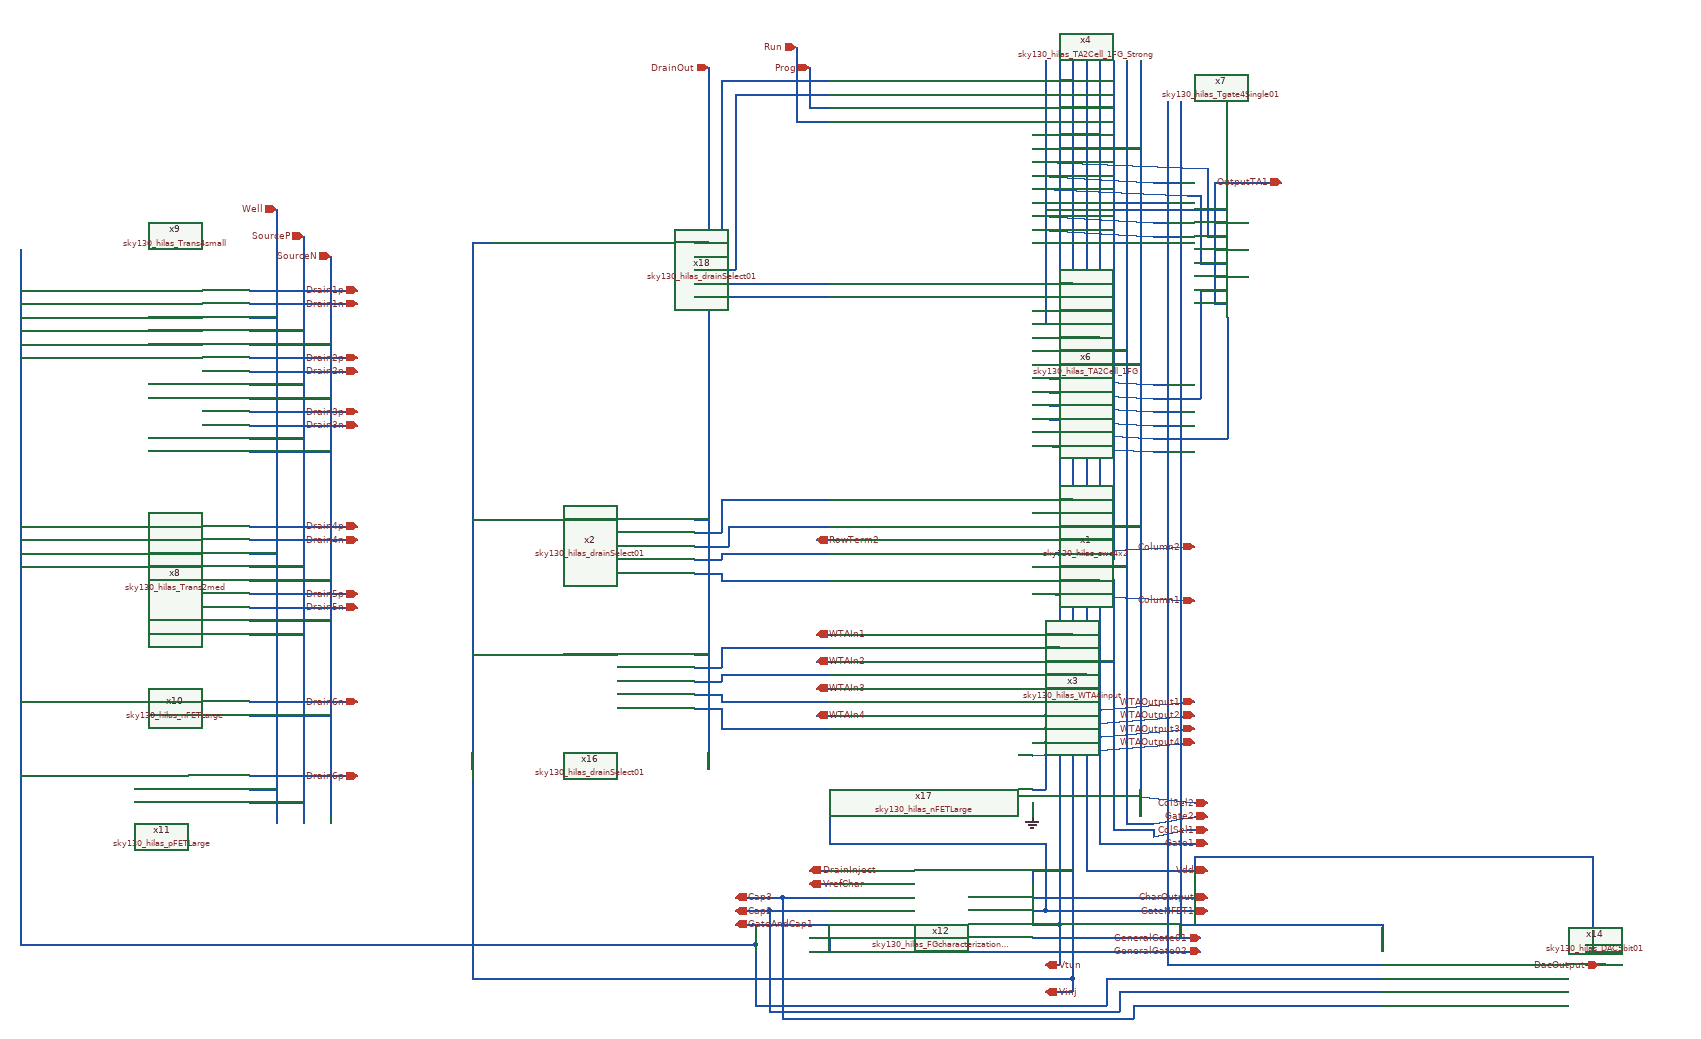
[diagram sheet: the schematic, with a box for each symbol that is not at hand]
v {xschem version=2.9.9 file_version=1.2 }
G {}
K {}
V {}
S {}
E {}
N 370 -10 370 440 { lab=Vtun}
N -500 -10 -500 430 { lab=Vinj}
N 390 -10 390 440 { lab=Vinj}
N -500 60 -470 60 { lab=Vinj}
N -500 260 -470 260 { lab=Vinj}
N 330 30 390 30 { lab=Vinj}
N 330 230 390 230 { lab=Vinj}
N 330 50 370 50 { lab=Vtun}
N 330 250 370 250 { lab=Vtun}
N 410 -10 410 440 { lab=Vdd}
N 330 290 410 290 { lab=Vdd}
N 330 480 330 500 { lab=GND}
N 330 330 350 330 { lab=#net1}
N 350 330 350 460 { lab=#net1}
N 330 460 350 460 { lab=#net1}
N -150 -10 -150 430 { lab=DrainOut}
N -170 60 -150 60 { lab=DrainOut}
N -170 260 -150 260 { lab=DrainOut}
N -130 30 30 30 { lab=#net2}
N -130 30 -130 80 { lab=#net2}
N -170 80 -130 80 { lab=#net2}
N -130 150 30 150 { lab=#net3}
N -130 140 -130 150 { lab=#net3}
N -170 140 -130 140 { lab=#net3}
N -130 110 30 110 { lab=#net4}
N -130 110 -130 120 { lab=#net4}
N -170 120 -130 120 { lab=#net4}
N -120 70 30 70 { lab=#net5}
N -120 70 -120 100 { lab=#net5}
N -170 100 -120 100 { lab=#net5}
N -130 250 30 250 { lab=#net6}
N -130 370 30 370 { lab=#net7}
N -110 330 30 330 { lab=#net8}
N -110 290 30 290 { lab=#net9}
N -170 280 -130 280 { lab=#net6}
N -130 250 -130 280 { lab=#net6}
N -170 340 -130 340 { lab=#net7}
N -130 340 -130 370 { lab=#net7}
N -130 330 -110 330 { lab=#net8}
N -130 320 -130 330 { lab=#net8}
N -170 320 -130 320 { lab=#net8}
N -130 290 -110 290 { lab=#net9}
N -130 290 -130 300 { lab=#net9}
N -170 300 -130 300 { lab=#net9}
N 430 -10 430 500 { lab=Gate1}
N 470 -10 470 500 { lab=Gate2}
N 330 310 430 310 { lab=Gate1}
N 330 150 430 150 { lab=Gate1}
N 330 130 450 130 { lab=Gate2}
N 490 -10 490 500 { lab=ColSel2}
N 450 130 470 130 { lab=Gate2}
N 450 -10 450 120 { lab=ColSel1}
N 450 150 450 500 { lab=ColSel1}
N 330 90 450 90 { lab=ColSel1}
N 330 270 450 270 { lab=ColSel1}
N 330 70 490 70 { lab=ColSel2}
N 440 120 450 150 { lab=ColSel1}
N 440 120 450 120 { lab=ColSel1}
N -500 420 -500 550 { lab=Vinj}
N -500 740 390 740 { lab=Vinj}
N 390 440 390 550 { lab=Vinj}
N 390 550 390 720 { lab=Vinj}
N -500 550 -500 720 { lab=Vinj}
N 370 440 370 660 { lab=Vtun}
N 330 660 370 660 { lab=Vtun}
N 330 580 390 580 { lab=Vinj}
N 390 720 390 740 { lab=Vinj}
N 370 660 370 720 { lab=Vtun}
N 350 720 370 720 { lab=Vtun}
N 390 740 390 760 { lab=Vinj}
N 350 760 390 760 { lab=Vinj}
N 30 460 30 540 { lab=GateNFET1}
N 30 540 350 540 { lab=GateNFET1}
N 350 540 350 640 { lab=GateNFET1}
N 330 640 350 640 { lab=GateNFET1}
N 350 640 590 640 { lab=GateNFET1}
N 330 620 570 620 { lab=CharOutput}
N 330 580 330 600 { lab=Vinj}
N 0 700 330 700 { lab=GeneralGate02}
N -0 680 30 680 { lab=GeneralGate02}
N -0 660 30 660 { lab=GateAndCap1}
N -0 640 30 640 { lab=Cap2}
N -0 620 30 620 { lab=Cap3}
N -0 600 30 600 { lab=VrefChar}
N 0 580 30 580 { lab=DrainInject}
N 370 -520 370 -70 { lab=Vtun}
N 390 -520 390 -70 { lab=Vinj}
N 410 -520 410 -70 { lab=Vdd}
N 430 -520 430 -10 { lab=Gate1}
N 470 -520 470 -10 { lab=Gate2}
N 490 -520 490 -10 { lab=ColSel2}
N 450 -520 450 -10 { lab=ColSel1}
N 370 -70 370 -10 { lab=Vtun}
N 390 -70 390 -10 { lab=Vinj}
N 410 -70 410 -10 { lab=Vdd}
N -150 -450 -150 -10 { lab=DrainOut}
N -150 -610 -150 -450 { lab=DrainOut}
N -170 -350 -150 -350 { lab=DrainOut}
N -130 -270 30 -270 { lab=#net10}
N -130 -290 30 -290 { lab=#net11}
N -170 -290 -130 -290 { lab=#net11}
N -170 -270 -130 -270 { lab=#net10}
N -500 -350 -500 -10 { lab=Vinj}
N -500 -350 -470 -350 { lab=Vinj}
N -0 -610 -0 -550 { lab=Prog}
N -20 -610 -20 -530 { lab=Run}
N 0 -550 30 -550 { lab=Prog}
N -20 -530 30 -530 { lab=Run}
N -170 -330 -130 -330 { lab=#net12}
N -130 -590 -130 -330 { lab=#net12}
N -130 -590 30 -590 { lab=#net12}
N -170 -310 -110 -310 { lab=#net13}
N -110 -570 -110 -310 { lab=#net13}
N -110 -570 30 -570 { lab=#net13}
N 370 -620 370 -520 { lab=Vtun}
N 390 -620 390 -520 { lab=Vinj}
N 410 -620 410 -520 { lab=Vdd}
N 430 -620 430 -520 { lab=Gate1}
N 450 -620 450 -520 { lab=ColSel1}
N 470 -620 470 -520 { lab=Gate2}
N 490 -620 490 -520 { lab=ColSel2}
N 330 -590 390 -590 { lab=Vinj}
N 330 -570 370 -570 { lab=Vtun}
N 330 -290 390 -290 { lab=Vinj}
N 330 -270 370 -270 { lab=Vtun}
N 330 -250 450 -250 { lab=ColSel1}
N 330 -550 450 -550 { lab=ColSel1}
N 330 -490 490 -490 { lab=ColSel2}
N 330 -170 490 -170 { lab=ColSel2}
N 330 -510 430 -510 { lab=Gate1}
N 330 -210 430 -210 { lab=Gate1}
N 330 -190 470 -190 { lab=Gate2}
N 330 -350 470 -350 { lab=Gate2}
N 350 -620 350 -230 { lab=#net14}
N 330 -230 350 -230 { lab=#net14}
N 330 -530 350 -530 { lab=#net14}
N 600 -440 600 -260 { lab=OutputTA1}
N 600 -260 620 -260 { lab=OutputTA1}
N 600 -300 620 -300 { lab=OutputTA1}
N 600 -340 620 -340 { lab=OutputTA1}
N 600 -380 620 -380 { lab=OutputTA1}
N 350 -400 620 -400 { lab=#net14}
N 620 -240 620 -60 { lab=#net15}
N 330 -70 350 -70 { lab=#net15}
N 350 -70 510 -60 { lab=#net15}
N 510 -60 620 -60 { lab=#net15}
N 330 -130 510 -120 { lab=#net16}
N 510 -120 580 -120 { lab=#net16}
N 580 -280 580 -120 { lab=#net16}
N 580 -280 620 -280 { lab=#net16}
N 590 -460 590 -360 { lab=#net17}
N 330 -470 590 -460 { lab=#net17}
N 330 -430 560 -420 { lab=#net18}
N 590 -360 620 -360 { lab=#net17}
N 580 -320 620 -320 { lab=#net18}
N 580 -420 580 -320 { lab=#net18}
N 560 -420 580 -420 { lab=#net18}
N 600 -440 680 -440 { lab=OutputTA1}
N 680 -440 700 -440 { lab=OutputTA1}
N 330 680 580 680 { lab=GeneralGate01}
N 330 700 580 700 { lab=GeneralGate02}
N 30 680 30 700 { lab=GeneralGate02}
N 570 620 590 620 { lab=CharOutput}
N 530 -560 530 520 { lab=GeneralGate02}
N 550 -560 550 520 { lab=GeneralGate01}
N 550 520 550 680 { lab=GeneralGate01}
N 530 520 530 700 { lab=GeneralGate02}
N 410 440 410 580 { lab=Vdd}
N 410 580 590 580 { lab=Vdd}
N -500 720 -500 740 { lab=Vinj}
N 330 -50 510 -40 { lab=GeneralGate02}
N 510 -40 530 -40 { lab=GeneralGate02}
N 330 -90 510 -80 { lab=GeneralGate01}
N 510 -80 550 -80 { lab=GeneralGate01}
N 330 -110 510 -100 { lab=GeneralGate01}
N 510 -100 550 -100 { lab=GeneralGate01}
N 330 -150 510 -140 { lab=GeneralGate02}
N 510 -140 530 -140 { lab=GeneralGate02}
N 330 -450 510 -440 { lab=GeneralGate01}
N 510 -440 550 -440 { lab=GeneralGate01}
N 330 -370 510 -360 { lab=GeneralGate01}
N 510 -360 550 -360 { lab=GeneralGate01}
N 330 -390 510 -380 { lab=GeneralGate02}
N 510 -380 530 -380 { lab=GeneralGate02}
N 330 -410 530 -410 { lab=GeneralGate02}
N 430 540 590 540 { lab=Gate1}
N 430 500 430 540 { lab=Gate1}
N 450 500 450 520 { lab=ColSel1}
N 450 520 510 520 { lab=ColSel1}
N 470 500 470 510 { lab=Gate2}
N 470 510 510 510 { lab=Gate2}
N 570 480 590 480 { lab=ColSel2}
N 490 470 570 480 { lab=ColSel2}
N 570 500 590 500 { lab=Gate2}
N 510 510 570 500 { lab=Gate2}
N 560 520 590 520 { lab=ColSel1}
N 510 530 560 520 { lab=ColSel1}
N 510 520 510 530 { lab=ColSel1}
N -1170 -340 -1170 510 { lab=GateAndCap1}
N -1170 -280 -1130 -280 { lab=GateAndCap1}
N -1170 -260 -1130 -260 { lab=GateAndCap1}
N -1170 -240 -1130 -240 { lab=GateAndCap1}
N -1170 -220 -1130 -220 { lab=GateAndCap1}
N -1170 -200 -1130 -200 { lab=GateAndCap1}
N -1170 -180 -1130 -180 { lab=GateAndCap1}
N -1170 70 -1130 70 { lab=GateAndCap1}
N -1170 90 -1130 90 { lab=GateAndCap1}
N -1170 110 -1130 110 { lab=GateAndCap1}
N -1170 130 -1130 130 { lab=GateAndCap1}
N -1170 330 -1130 330 { lab=GateAndCap1}
N -1170 440 -1130 440 { lab=GateAndCap1}
N -790 -310 -790 510 { lab=Well}
N -750 -310 -750 510 { lab=SourceP}
N -710 -310 -710 500 { lab=SourceN}
N -830 -240 -790 -240 { lab=Well}
N -830 110 -790 110 { lab=Well}
N -830 460 -790 460 { lab=Well}
N -830 -220 -750 -220 { lab=SourceP}
N -830 -200 -710 -200 { lab=SourceN}
N -830 -140 -750 -140 { lab=SourceP}
N -830 -120 -710 -120 { lab=SourceN}
N -830 -60 -750 -60 { lab=SourceP}
N -830 -40 -710 -40 { lab=SourceN}
N -830 130 -750 130 { lab=SourceP}
N -830 150 -710 150 { lab=SourceN}
N -830 230 -750 230 { lab=SourceP}
N -830 210 -710 210 { lab=SourceN}
N -830 350 -710 350 { lab=SourceN}
N -830 480 -750 480 { lab=SourceP}
N -110 660 0 660 { lab=GateAndCap1}
N -80 660 -80 690 { lab=GateAndCap1}
N -470 690 -80 690 { lab=GateAndCap1}
N -540 690 -470 690 { lab=GateAndCap1}
N -1170 690 -540 690 { lab=GateAndCap1}
N -1170 510 -1170 690 { lab=GateAndCap1}
N -830 -280 -670 -280 { lab=Drain1p}
N -830 -260 -670 -260 { lab=Drain1n}
N -830 -180 -670 -180 { lab=Drain2p}
N -830 -160 -670 -160 { lab=Drain2n}
N -830 -100 -670 -100 { lab=Drain3p}
N -830 -80 -670 -80 { lab=Drain3n}
N -830 70 -670 70 { lab=Drain4p}
N -830 90 -670 90 { lab=Drain4n}
N -830 170 -670 170 { lab=Drain5p}
N -830 190 -670 190 { lab=Drain5n}
N -830 330 -670 330 { lab=Drain6n}
N -830 440 -670 440 { lab=Drain6p}
N -710 -330 -710 -310 { lab=SourceN}
N -750 -360 -750 -310 { lab=SourceP}
N -790 -400 -790 -310 { lab=Well}
N -20 -640 -20 -610 { lab=Run}
N 10 270 30 270 { lab=WTAIn2}
N 10 230 30 230 { lab=WTAIn1}
N 10 310 30 310 { lab=WTAIn3}
N 10 350 30 350 { lab=WTAIn4}
N 330 110 570 100 { lab=Column2}
N 330 170 570 180 { lab=Column1}
N 570 560 570 580 { lab=Vdd}
N 570 560 1160 560 { lab=Vdd}
N 1160 560 1160 690 { lab=Vdd}
N 1150 690 1160 690 { lab=Vdd}
N 550 660 850 660 { lab=GeneralGate01}
N 530 700 530 720 { lab=GeneralGate02}
N 530 720 840 720 { lab=GeneralGate02}
N 840 720 850 720 { lab=GeneralGate02}
N 850 660 850 700 { lab=GeneralGate01}
N 1150 700 1160 700 { lab=Vdd}
N 1160 670 1160 700 { lab=Vdd}
N 440 740 850 740 { lab=GateAndCap1}
N 440 740 440 780 { lab=GateAndCap1}
N -80 780 440 780 { lab=GateAndCap1}
N -80 690 -80 780 { lab=GateAndCap1}
N 460 760 850 760 { lab=Cap2}
N 460 760 460 790 { lab=Cap2}
N -60 790 460 790 { lab=Cap2}
N -60 640 -60 790 { lab=Cap2}
N -60 640 -0 640 { lab=Cap2}
N -110 640 -60 640 { lab=Cap2}
N 480 780 850 780 { lab=Cap3}
N 480 780 480 800 { lab=Cap3}
N -40 800 480 800 { lab=Cap3}
N -40 620 -40 800 { lab=Cap3}
N -40 620 0 620 { lab=Cap3}
N -110 620 -40 620 { lab=Cap3}
N 1150 720 1180 720 { lab=DacOutput}
N 330 350 570 330 { lab=WTAOutput1}
N 330 370 570 350 { lab=WTAOutput2}
N 330 390 570 370 { lab=WTAOutput3}
N 330 410 570 390 { lab=WTAOutput4}
N 10 90 30 90 { lab=RowTerm2}
C {sky130_hilas_swc4x2.sym} 180 100 0 0 {name=x1}
C {sky130_hilas_drainSelect01.sym} -320 100 0 0 {name=x2}
C {sky130_hilas_WTA4input.sym} 180 320 0 0 {name=x3}
C {sky130_hilas_TA2Cell_1FG_Strong.sym} 180 -470 0 0 {name=x4}
C {sky130_hilas_TA2Cell_1FG.sym} 180 -170 0 0 {name=x6}
C {sky130_hilas_Tgate4Single01.sym} 770 -320 0 1 {name=x7}
C {sky130_hilas_Trans2med.sym} -980 150 0 0 {name=x8}
C {sky130_hilas_Trans4small.sym} -980 -160 0 0 {name=x9}
C {sky130_hilas_nFETLarge.sym} -980 340 0 0 {name=x10}
C {sky130_hilas_pFETLarge.sym} -980 460 0 0 {name=x11}
C {sky130_hilas_FGcharacterization01.sym} 180 630 0 0 {name=x12}
C {sky130_hilas_DAC5bit01.sym} 1000 740 0 0 {name=x14}
C {sky130_hilas_drainSelect01.sym} -320 300 0 0 {name=x16}
C {devices/gnd.sym} 330 500 0 0 {name=l1 lab=GND}
C {sky130_hilas_nFETLarge.sym} 180 470 0 0 {name=x17}
C {sky130_hilas_drainSelect01.sym} -320 -310 0 0 {name=x18}
C {devices/iopin.sym} 350 720 0 1 {name=Vtun lab=Vtun}
C {devices/iopin.sym} 350 760 0 1 {name=Vinj lab=Vinj}
C {devices/iopin.sym} 590 640 0 0 {name=GateNFET1 lab=GateNFET1}
C {devices/iopin.sym} 590 620 0 0 {name=CharOutput lab=CharOutput}
C {devices/iopin.sym} 0 580 0 1 {name=DrainInject lab=DrainInject}
C {devices/iopin.sym} 0 600 0 1 {name=VrefChar lab=VrefChar}
C {devices/iopin.sym} -110 620 0 1 {name=Cap3 lab=Cap3}
C {devices/iopin.sym} -110 640 0 1 {name=Cap2 lab=Cap2}
C {devices/iopin.sym} -110 660 0 1 {name=GateAndCap1 lab=GateAndCap1}
C {devices/iopin.sym} 580 680 0 0 {name=GeneralGate01 lab=GeneralGate01}
C {devices/iopin.sym} 580 700 0 0 {name=GeneralGate02 lab=GeneralGate02}
C {devices/iopin.sym} 700 -440 0 0 {name=OutputTA1 lab=OutputTA1}
C {devices/iopin.sym} 590 580 0 0 {name=Vdd lab=Vdd}
C {devices/iopin.sym} 590 540 0 0 {name=Gate1 lab=Gate1}
C {devices/iopin.sym} 590 520 0 0 {name=ColSel1 lab=ColSel1}
C {devices/iopin.sym} 590 500 0 0 {name=Gate2 lab=Gate2}
C {devices/iopin.sym} 590 480 0 0 {name=ColSel2 lab=ColSel2}
C {devices/iopin.sym} -670 -280 0 0 {name=Drain1p lab=Drain1p}
C {devices/iopin.sym} -670 -260 0 0 {name=Drain1n lab=Drain1n}
C {devices/iopin.sym} -670 -180 0 0 {name=Drain2p lab=Drain2p}
C {devices/iopin.sym} -670 -160 0 0 {name=Drain2n lab=Drain2n}
C {devices/iopin.sym} -670 -100 0 0 {name=Drain3p lab=Drain3p}
C {devices/iopin.sym} -670 -80 0 0 {name=Drain3n lab=Drain3n}
C {devices/iopin.sym} -670 70 0 0 {name=Drain4p lab=Drain4p}
C {devices/iopin.sym} -670 90 0 0 {name=Drain4n lab=Drain4n}
C {devices/iopin.sym} -670 170 0 0 {name=Drain5p lab=Drain5p}
C {devices/iopin.sym} -670 190 0 0 {name=Drain5n lab=Drain5n}
C {devices/iopin.sym} -670 440 0 0 {name=Drain6p lab=Drain6p}
C {devices/iopin.sym} -670 330 0 0 {name=Drain16n lab=Drain6n}
C {devices/iopin.sym} -710 -330 0 0 {name=SourceN lab=SourceN}
C {devices/iopin.sym} -750 -360 0 0 {name=SourceP lab=SourceP}
C {devices/iopin.sym} -790 -400 0 0 {name=Well lab=Well}
C {devices/iopin.sym} -20 -640 0 0 {name=Run lab=Run}
C {devices/iopin.sym} 0 -610 0 0 {name=Prog lab=Prog}
C {devices/iopin.sym} -150 -610 0 0 {name=DrainOut lab=DrainOut}
C {devices/iopin.sym} 10 270 0 1 {name=WTAIn2 lab=WTAIn2}
C {devices/iopin.sym} 10 230 0 1 {name=WTAIn1 lab=WTAIn1}
C {devices/iopin.sym} 10 310 0 1 {name=WTAIn3 lab=WTAIn3}
C {devices/iopin.sym} 10 350 0 1 {name=WTAIn4 lab=WTAIn4}
C {devices/iopin.sym} 10 90 0 1 {name=RowTerm2 lab=RowTerm2}
C {devices/iopin.sym} 570 180 0 0 {name=Column1 lab=Column1}
C {devices/iopin.sym} 570 100 0 0 {name=Column2 lab=Column2}
C {devices/iopin.sym} 1170 720 0 0 {name=DacOutput lab=DacOutput}
C {devices/iopin.sym} 570 330 0 0 {name=WTAOutput1 lab=WTAOutput1}
C {devices/iopin.sym} 570 350 0 0 {name=WTAOutput2 lab=WTAOutput2}
C {devices/iopin.sym} 570 370 0 0 {name=WTAOutput3 lab=WTAOutput3}
C {devices/iopin.sym} 570 390 0 0 {name=WTAOutput4 lab=WTAOutput4}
